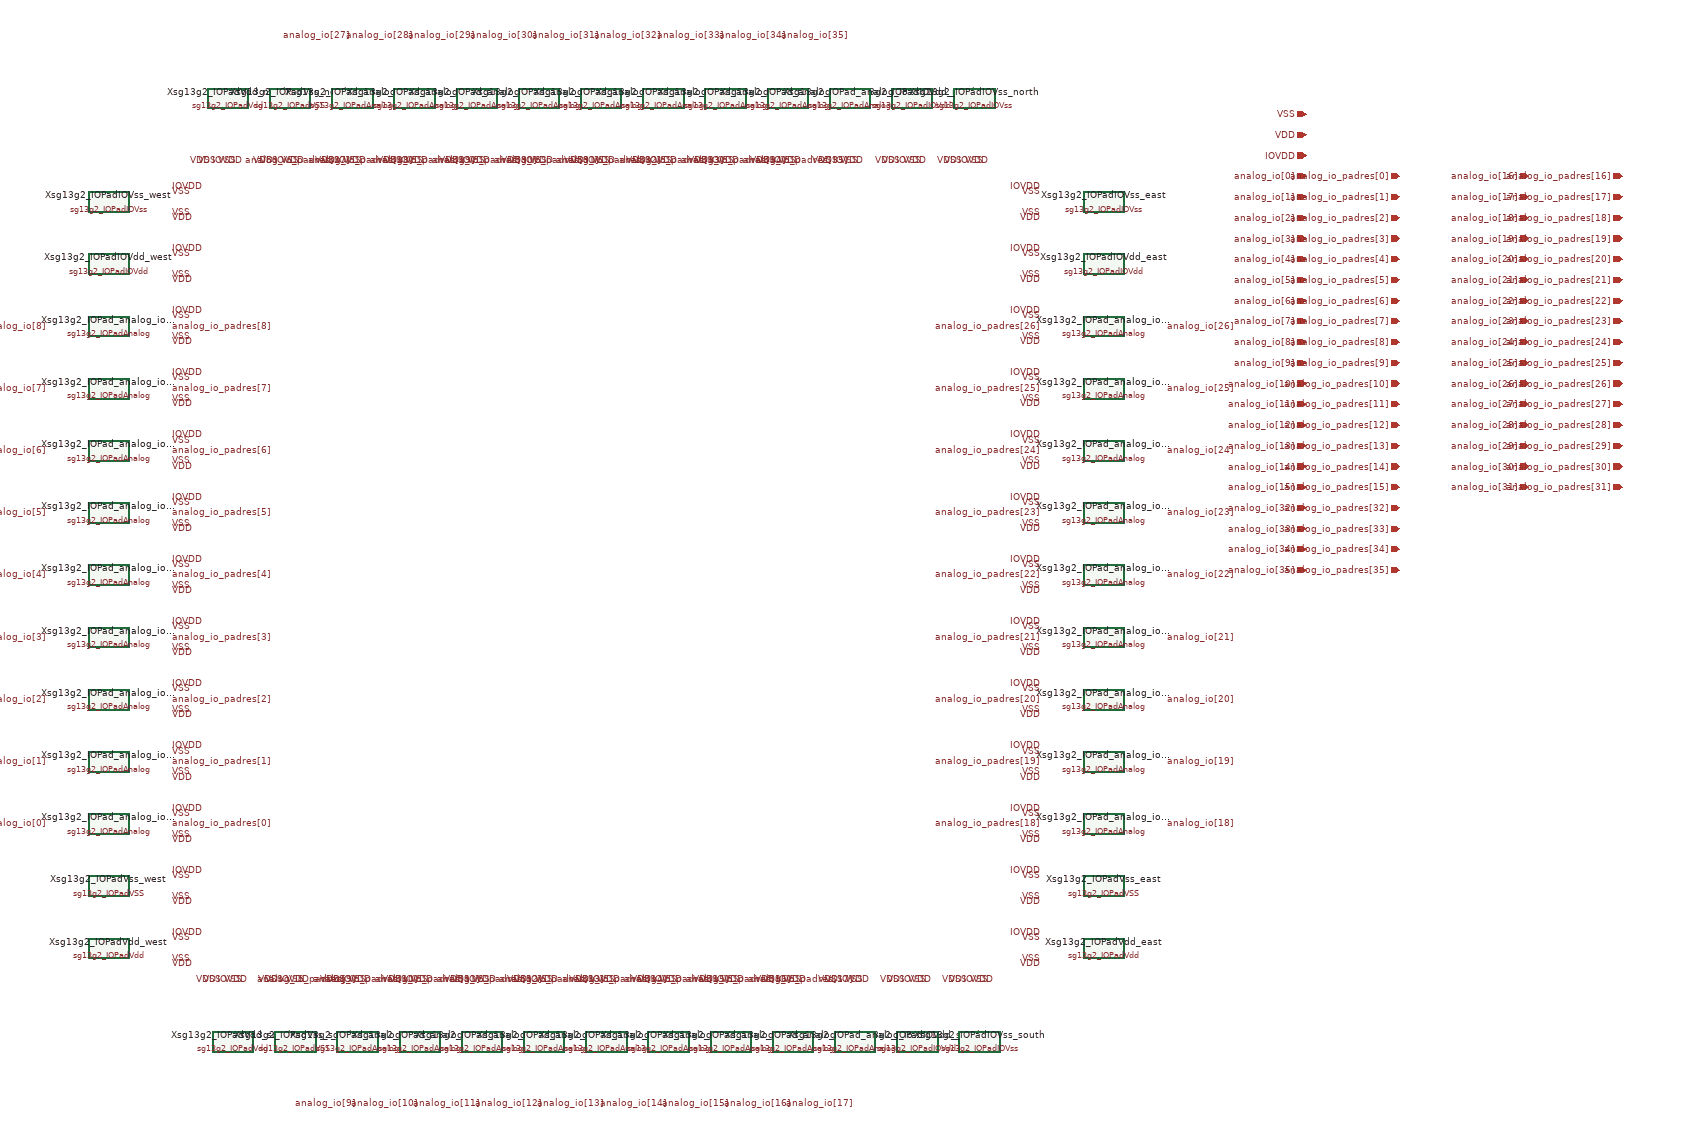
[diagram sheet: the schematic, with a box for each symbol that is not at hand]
v {xschem version=3.4.6 file_version=1.2}
G {}
K {}
V {}
S {}
E {}
C {sg13g2_io/xschem/sg13g2_IOPadVdd.sym} 160 -400 0 1 {name=Xsg13g2_IOPadVdd_west}
C {sg13g2_io/xschem/sg13g2_IOPadVSS.sym} 160 -520 0 1 {name=Xsg13g2_IOPadVss_west}
C {sg13g2_io/xschem/sg13g2_IOPadAnalog.sym} 160 -640 0 1 {name=Xsg13g2_IOPad_analog_io[0]}
C {sg13g2_io/xschem/sg13g2_IOPadAnalog.sym} 160 -760 0 1 {name=Xsg13g2_IOPad_analog_io[1]}
C {sg13g2_io/xschem/sg13g2_IOPadAnalog.sym} 160 -880 0 1 {name=Xsg13g2_IOPad_analog_io[2]}
C {sg13g2_io/xschem/sg13g2_IOPadAnalog.sym} 160 -1000 0 1 {name=Xsg13g2_IOPad_analog_io[3]}
C {sg13g2_io/xschem/sg13g2_IOPadAnalog.sym} 160 -1120 0 1 {name=Xsg13g2_IOPad_analog_io[4]}
C {sg13g2_io/xschem/sg13g2_IOPadAnalog.sym} 160 -1240 0 1 {name=Xsg13g2_IOPad_analog_io[5]}
C {sg13g2_io/xschem/sg13g2_IOPadAnalog.sym} 160 -1360 0 1 {name=Xsg13g2_IOPad_analog_io[6]}
C {sg13g2_io/xschem/sg13g2_IOPadAnalog.sym} 160 -1480 0 1 {name=Xsg13g2_IOPad_analog_io[7]}
C {sg13g2_io/xschem/sg13g2_IOPadIOVdd.sym} 160 -1720 0 1 {name=Xsg13g2_IOPadIOVdd_west}
C {sg13g2_io/xschem/sg13g2_IOPadIOVss.sym} 160 -1840 0 1 {name=Xsg13g2_IOPadIOVss_west}
C {sg13g2_io/xschem/sg13g2_IOPadVdd.sym} 400 -220 1 0 {name=Xsg13g2_IOPadVdd_south}
C {sg13g2_io/xschem/sg13g2_IOPadVSS.sym} 520 -220 1 0 {name=Xsg13g2_IOPadVss_south}
C {sg13g2_io/xschem/sg13g2_IOPadAnalog.sym} 640 -220 1 0 {name=Xsg13g2_IOPad_analog_io[9]}
C {sg13g2_io/xschem/sg13g2_IOPadAnalog.sym} 760 -220 1 0 {name=Xsg13g2_IOPad_analog_io[10]}
C {sg13g2_io/xschem/sg13g2_IOPadAnalog.sym} 880 -220 1 0 {name=Xsg13g2_IOPad_analog_io[11]}
C {sg13g2_io/xschem/sg13g2_IOPadAnalog.sym} 1000 -220 1 0 {name=Xsg13g2_IOPad_analog_io[12]}
C {sg13g2_io/xschem/sg13g2_IOPadAnalog.sym} 1120 -220 1 0 {name=Xsg13g2_IOPad_analog_io[13]}
C {sg13g2_io/xschem/sg13g2_IOPadAnalog.sym} 1240 -220 1 0 {name=Xsg13g2_IOPad_analog_io[14]}
C {sg13g2_io/xschem/sg13g2_IOPadAnalog.sym} 1360 -220 1 0 {name=Xsg13g2_IOPad_analog_io[15]}
C {sg13g2_io/xschem/sg13g2_IOPadIOVdd.sym} 1720 -220 1 0 {name=Xsg13g2_IOPadIOVdd_south}
C {sg13g2_io/xschem/sg13g2_IOPadIOVss.sym} 1840 -220 1 0 {name=Xsg13g2_IOPadIOVss_south}
C {sg13g2_io/xschem/sg13g2_IOPadAnalog.sym} 160 -1600 0 1 {name=Xsg13g2_IOPad_analog_io[8]}
C {sg13g2_io/xschem/sg13g2_IOPadAnalog.sym} 1480 -220 1 0 {name=Xsg13g2_IOPad_analog_io[16]}
C {sg13g2_io/xschem/sg13g2_IOPadAnalog.sym} 1600 -220 1 0 {name=Xsg13g2_IOPad_analog_io[17]}
C {sg13g2_io/xschem/sg13g2_IOPadVdd.sym} 2080 -400 0 0 {name=Xsg13g2_IOPadVdd_east}
C {sg13g2_io/xschem/sg13g2_IOPadVSS.sym} 2080 -520 0 0 {name=Xsg13g2_IOPadVss_east}
C {sg13g2_io/xschem/sg13g2_IOPadAnalog.sym} 2080 -640 0 0 {name=Xsg13g2_IOPad_analog_io[18]}
C {sg13g2_io/xschem/sg13g2_IOPadAnalog.sym} 2080 -760 0 0 {name=Xsg13g2_IOPad_analog_io[19]}
C {sg13g2_io/xschem/sg13g2_IOPadAnalog.sym} 2080 -880 0 0 {name=Xsg13g2_IOPad_analog_io[20]}
C {sg13g2_io/xschem/sg13g2_IOPadAnalog.sym} 2080 -1000 0 0 {name=Xsg13g2_IOPad_analog_io[21]}
C {sg13g2_io/xschem/sg13g2_IOPadAnalog.sym} 2080 -1120 0 0 {name=Xsg13g2_IOPad_analog_io[22]}
C {sg13g2_io/xschem/sg13g2_IOPadAnalog.sym} 2080 -1240 0 0 {name=Xsg13g2_IOPad_analog_io[23]}
C {sg13g2_io/xschem/sg13g2_IOPadAnalog.sym} 2080 -1360 0 0 {name=Xsg13g2_IOPad_analog_io[24]}
C {sg13g2_io/xschem/sg13g2_IOPadAnalog.sym} 2080 -1480 0 0 {name=Xsg13g2_IOPad_analog_io[25]}
C {sg13g2_io/xschem/sg13g2_IOPadIOVdd.sym} 2080 -1720 0 0 {name=Xsg13g2_IOPadIOVdd_east}
C {sg13g2_io/xschem/sg13g2_IOPadIOVss.sym} 2080 -1840 0 0 {name=Xsg13g2_IOPadIOVss_east}
C {sg13g2_io/xschem/sg13g2_IOPadAnalog.sym} 2080 -1600 0 0 {name=Xsg13g2_IOPad_analog_io[26]}
C {sg13g2_io/xschem/sg13g2_IOPadVdd.sym} 390 -2040 1 1 {name=Xsg13g2_IOPadVdd_north}
C {sg13g2_io/xschem/sg13g2_IOPadVSS.sym} 510 -2040 1 1 {name=Xsg13g2_IOPadVss_north}
C {sg13g2_io/xschem/sg13g2_IOPadAnalog.sym} 630 -2040 1 1 {name=Xsg13g2_IOPad_analog_io[28]}
C {sg13g2_io/xschem/sg13g2_IOPadAnalog.sym} 750 -2040 1 1 {name=Xsg13g2_IOPad_analog_io[29]}
C {sg13g2_io/xschem/sg13g2_IOPadAnalog.sym} 870 -2040 1 1 {name=Xsg13g2_IOPad_analog_io[30]}
C {sg13g2_io/xschem/sg13g2_IOPadAnalog.sym} 990 -2040 1 1 {name=Xsg13g2_IOPad_analog_io[31]}
C {sg13g2_io/xschem/sg13g2_IOPadAnalog.sym} 1110 -2040 1 1 {name=Xsg13g2_IOPad_analog_io[32]}
C {sg13g2_io/xschem/sg13g2_IOPadAnalog.sym} 1230 -2040 1 1 {name=Xsg13g2_IOPad_analog_io[33]}
C {sg13g2_io/xschem/sg13g2_IOPadAnalog.sym} 1350 -2040 1 1 {name=Xsg13g2_IOPad_analog_io[34]}
C {sg13g2_io/xschem/sg13g2_IOPadAnalog.sym} 1470 -2040 1 1 {name=Xsg13g2_IOPad_analog_io[35]}
C {sg13g2_io/xschem/sg13g2_IOPadIOVdd.sym} 1710 -2040 1 1 {name=Xsg13g2_IOPadIOVdd_north}
C {sg13g2_io/xschem/sg13g2_IOPadIOVss.sym} 1830 -2040 1 1 {name=Xsg13g2_IOPadIOVss_north}
C {sg13g2_io/xschem/sg13g2_IOPadAnalog.sym} 1590 -2040 1 1 {name=Xsg13g2_IOPad_analog_io[27]}
C {lab_pin.sym} 280 -430 0 1 {name=p1 lab=IOVDD}
C {lab_pin.sym} 280 -420 0 1 {name=p2 lab=VSS}
C {lab_pin.sym} 280 -380 0 1 {name=p3 lab=VSS}
C {lab_pin.sym} 280 -370 0 1 {name=p4 lab=VDD}
C {lab_pin.sym} 280 -550 0 1 {name=p5 lab=IOVDD}
C {lab_pin.sym} 280 -540 0 1 {name=p6 lab=VSS}
C {lab_pin.sym} 280 -500 0 1 {name=p7 lab=VSS}
C {lab_pin.sym} 280 -490 0 1 {name=p8 lab=VDD}
C {lab_pin.sym} 280 -670 0 1 {name=p9 lab=IOVDD}
C {lab_pin.sym} 280 -660 0 1 {name=p10 lab=VSS}
C {lab_pin.sym} 280 -640 0 1 {name=p11 lab=analog_io_padres[0]}
C {lab_pin.sym} 280 -620 0 1 {name=p12 lab=VSS}
C {lab_pin.sym} 280 -610 0 1 {name=p13 lab=VDD}
C {lab_pin.sym} 40 -640 0 0 {name=p14 lab=analog_io[0]}
C {lab_pin.sym} 280 -790 0 1 {name=p15 lab=IOVDD}
C {lab_pin.sym} 280 -780 0 1 {name=p16 lab=VSS}
C {lab_pin.sym} 280 -760 0 1 {name=p17 lab=analog_io_padres[1]}
C {lab_pin.sym} 280 -740 0 1 {name=p18 lab=VSS}
C {lab_pin.sym} 280 -730 0 1 {name=p19 lab=VDD}
C {lab_pin.sym} 40 -760 0 0 {name=p20 lab=analog_io[1]}
C {lab_pin.sym} 280 -910 0 1 {name=p21 lab=IOVDD}
C {lab_pin.sym} 280 -900 0 1 {name=p22 lab=VSS}
C {lab_pin.sym} 280 -880 0 1 {name=p23 lab=analog_io_padres[2]}
C {lab_pin.sym} 280 -860 0 1 {name=p24 lab=VSS}
C {lab_pin.sym} 280 -850 0 1 {name=p25 lab=VDD}
C {lab_pin.sym} 40 -880 0 0 {name=p26 lab=analog_io[2]}
C {lab_pin.sym} 280 -1030 0 1 {name=p27 lab=IOVDD}
C {lab_pin.sym} 280 -1020 0 1 {name=p28 lab=VSS}
C {lab_pin.sym} 280 -1000 0 1 {name=p29 lab=analog_io_padres[3]}
C {lab_pin.sym} 280 -980 0 1 {name=p30 lab=VSS}
C {lab_pin.sym} 280 -970 0 1 {name=p31 lab=VDD}
C {lab_pin.sym} 40 -1000 0 0 {name=p32 lab=analog_io[3]}
C {lab_pin.sym} 280 -1150 0 1 {name=p33 lab=IOVDD}
C {lab_pin.sym} 280 -1140 0 1 {name=p34 lab=VSS}
C {lab_pin.sym} 280 -1120 0 1 {name=p35 lab=analog_io_padres[4]}
C {lab_pin.sym} 280 -1100 0 1 {name=p36 lab=VSS}
C {lab_pin.sym} 280 -1090 0 1 {name=p37 lab=VDD}
C {lab_pin.sym} 40 -1120 0 0 {name=p38 lab=analog_io[4]}
C {lab_pin.sym} 280 -1270 0 1 {name=p39 lab=IOVDD}
C {lab_pin.sym} 280 -1260 0 1 {name=p40 lab=VSS}
C {lab_pin.sym} 280 -1240 0 1 {name=p41 lab=analog_io_padres[5]}
C {lab_pin.sym} 280 -1220 0 1 {name=p42 lab=VSS}
C {lab_pin.sym} 280 -1210 0 1 {name=p43 lab=VDD}
C {lab_pin.sym} 40 -1240 0 0 {name=p44 lab=analog_io[5]}
C {lab_pin.sym} 280 -1390 0 1 {name=p45 lab=IOVDD}
C {lab_pin.sym} 280 -1380 0 1 {name=p46 lab=VSS}
C {lab_pin.sym} 280 -1360 0 1 {name=p47 lab=analog_io_padres[6]}
C {lab_pin.sym} 280 -1340 0 1 {name=p48 lab=VSS}
C {lab_pin.sym} 280 -1330 0 1 {name=p49 lab=VDD}
C {lab_pin.sym} 40 -1360 0 0 {name=p50 lab=analog_io[6]}
C {lab_pin.sym} 280 -1510 0 1 {name=p51 lab=IOVDD}
C {lab_pin.sym} 280 -1500 0 1 {name=p52 lab=VSS}
C {lab_pin.sym} 280 -1480 0 1 {name=p53 lab=analog_io_padres[7]}
C {lab_pin.sym} 280 -1460 0 1 {name=p54 lab=VSS}
C {lab_pin.sym} 280 -1450 0 1 {name=p55 lab=VDD}
C {lab_pin.sym} 40 -1480 0 0 {name=p56 lab=analog_io[7]}
C {lab_pin.sym} 280 -1750 0 1 {name=p57 lab=IOVDD}
C {lab_pin.sym} 280 -1740 0 1 {name=p58 lab=VSS}
C {lab_pin.sym} 280 -1700 0 1 {name=p59 lab=VSS}
C {lab_pin.sym} 280 -1690 0 1 {name=p60 lab=VDD}
C {lab_pin.sym} 280 -1870 0 1 {name=p61 lab=IOVDD}
C {lab_pin.sym} 280 -1860 0 1 {name=p62 lab=VSS}
C {lab_pin.sym} 280 -1820 0 1 {name=p63 lab=VSS}
C {lab_pin.sym} 280 -1810 0 1 {name=p64 lab=VDD}
C {lab_pin.sym} 430 -340 3 1 {name=p65 lab=IOVDD}
C {lab_pin.sym} 420 -340 3 1 {name=p66 lab=VSS}
C {lab_pin.sym} 380 -340 3 1 {name=p67 lab=VSS}
C {lab_pin.sym} 370 -340 3 1 {name=p68 lab=VDD}
C {lab_pin.sym} 550 -340 3 1 {name=p69 lab=IOVDD}
C {lab_pin.sym} 540 -340 3 1 {name=p70 lab=VSS}
C {lab_pin.sym} 500 -340 3 1 {name=p71 lab=VSS}
C {lab_pin.sym} 490 -340 3 1 {name=p72 lab=VDD}
C {lab_pin.sym} 670 -340 3 1 {name=p73 lab=IOVDD}
C {lab_pin.sym} 660 -340 3 1 {name=p74 lab=VSS}
C {lab_pin.sym} 640 -340 3 1 {name=p75 lab=analog_io_padres[9]}
C {lab_pin.sym} 620 -340 3 1 {name=p76 lab=VSS}
C {lab_pin.sym} 610 -340 3 1 {name=p77 lab=VDD}
C {lab_pin.sym} 640 -100 3 0 {name=p78 lab=analog_io[9]}
C {lab_pin.sym} 790 -340 3 1 {name=p79 lab=IOVDD}
C {lab_pin.sym} 780 -340 3 1 {name=p80 lab=VSS}
C {lab_pin.sym} 760 -340 3 1 {name=p81 lab=analog_io_padres[10]}
C {lab_pin.sym} 740 -340 3 1 {name=p82 lab=VSS}
C {lab_pin.sym} 730 -340 3 1 {name=p83 lab=VDD}
C {lab_pin.sym} 760 -100 3 0 {name=p84 lab=analog_io[10]}
C {lab_pin.sym} 910 -340 3 1 {name=p85 lab=IOVDD}
C {lab_pin.sym} 900 -340 3 1 {name=p86 lab=VSS}
C {lab_pin.sym} 880 -340 3 1 {name=p87 lab=analog_io_padres[11]}
C {lab_pin.sym} 860 -340 3 1 {name=p88 lab=VSS}
C {lab_pin.sym} 850 -340 3 1 {name=p89 lab=VDD}
C {lab_pin.sym} 880 -100 3 0 {name=p90 lab=analog_io[11]}
C {lab_pin.sym} 1030 -340 3 1 {name=p91 lab=IOVDD}
C {lab_pin.sym} 1020 -340 3 1 {name=p92 lab=VSS}
C {lab_pin.sym} 1000 -340 3 1 {name=p93 lab=analog_io_padres[12]}
C {lab_pin.sym} 980 -340 3 1 {name=p94 lab=VSS}
C {lab_pin.sym} 970 -340 3 1 {name=p95 lab=VDD}
C {lab_pin.sym} 1000 -100 3 0 {name=p96 lab=analog_io[12]}
C {lab_pin.sym} 1150 -340 3 1 {name=p97 lab=IOVDD}
C {lab_pin.sym} 1140 -340 3 1 {name=p98 lab=VSS}
C {lab_pin.sym} 1120 -340 3 1 {name=p99 lab=analog_io_padres[13]}
C {lab_pin.sym} 1100 -340 3 1 {name=p100 lab=VSS}
C {lab_pin.sym} 1090 -340 3 1 {name=p101 lab=VDD}
C {lab_pin.sym} 1120 -100 3 0 {name=p102 lab=analog_io[13]}
C {lab_pin.sym} 1270 -340 3 1 {name=p103 lab=IOVDD}
C {lab_pin.sym} 1260 -340 3 1 {name=p104 lab=VSS}
C {lab_pin.sym} 1240 -340 3 1 {name=p105 lab=analog_io_padres[14]}
C {lab_pin.sym} 1220 -340 3 1 {name=p106 lab=VSS}
C {lab_pin.sym} 1210 -340 3 1 {name=p107 lab=VDD}
C {lab_pin.sym} 1240 -100 3 0 {name=p108 lab=analog_io[14]}
C {lab_pin.sym} 1390 -340 3 1 {name=p109 lab=IOVDD}
C {lab_pin.sym} 1380 -340 3 1 {name=p110 lab=VSS}
C {lab_pin.sym} 1360 -340 3 1 {name=p111 lab=analog_io_padres[15]}
C {lab_pin.sym} 1340 -340 3 1 {name=p112 lab=VSS}
C {lab_pin.sym} 1330 -340 3 1 {name=p113 lab=VDD}
C {lab_pin.sym} 1360 -100 3 0 {name=p114 lab=analog_io[15]}
C {lab_pin.sym} 1750 -340 3 1 {name=p115 lab=IOVDD}
C {lab_pin.sym} 1740 -340 3 1 {name=p116 lab=VSS}
C {lab_pin.sym} 1700 -340 3 1 {name=p117 lab=VSS}
C {lab_pin.sym} 1690 -340 3 1 {name=p118 lab=VDD}
C {lab_pin.sym} 1870 -340 3 1 {name=p119 lab=IOVDD}
C {lab_pin.sym} 1860 -340 3 1 {name=p120 lab=VSS}
C {lab_pin.sym} 1820 -340 3 1 {name=p121 lab=VSS}
C {lab_pin.sym} 1810 -340 3 1 {name=p122 lab=VDD}
C {lab_pin.sym} 280 -1630 0 1 {name=p123 lab=IOVDD}
C {lab_pin.sym} 280 -1620 0 1 {name=p124 lab=VSS}
C {lab_pin.sym} 280 -1600 0 1 {name=p125 lab=analog_io_padres[8]}
C {lab_pin.sym} 280 -1580 0 1 {name=p126 lab=VSS}
C {lab_pin.sym} 280 -1570 0 1 {name=p127 lab=VDD}
C {lab_pin.sym} 40 -1600 0 0 {name=p128 lab=analog_io[8]}
C {lab_pin.sym} 1510 -340 3 1 {name=p129 lab=IOVDD}
C {lab_pin.sym} 1500 -340 3 1 {name=p130 lab=VSS}
C {lab_pin.sym} 1480 -340 3 1 {name=p131 lab=analog_io_padres[16]}
C {lab_pin.sym} 1460 -340 3 1 {name=p132 lab=VSS}
C {lab_pin.sym} 1450 -340 3 1 {name=p133 lab=VDD}
C {lab_pin.sym} 1480 -100 3 0 {name=p134 lab=analog_io[16]}
C {lab_pin.sym} 1630 -340 3 1 {name=p135 lab=IOVDD}
C {lab_pin.sym} 1620 -340 3 1 {name=p136 lab=VSS}
C {lab_pin.sym} 1600 -340 3 1 {name=p137 lab=analog_io_padres[17]}
C {lab_pin.sym} 1580 -340 3 1 {name=p138 lab=VSS}
C {lab_pin.sym} 1570 -340 3 1 {name=p139 lab=VDD}
C {lab_pin.sym} 1600 -100 3 0 {name=p140 lab=analog_io[17]}
C {lab_pin.sym} 1960 -430 0 0 {name=p141 lab=IOVDD}
C {lab_pin.sym} 1960 -420 0 0 {name=p142 lab=VSS}
C {lab_pin.sym} 1960 -380 0 0 {name=p143 lab=VSS}
C {lab_pin.sym} 1960 -370 0 0 {name=p144 lab=VDD}
C {lab_pin.sym} 1960 -550 0 0 {name=p145 lab=IOVDD}
C {lab_pin.sym} 1960 -540 0 0 {name=p146 lab=VSS}
C {lab_pin.sym} 1960 -500 0 0 {name=p147 lab=VSS}
C {lab_pin.sym} 1960 -490 0 0 {name=p148 lab=VDD}
C {lab_pin.sym} 1960 -670 0 0 {name=p149 lab=IOVDD}
C {lab_pin.sym} 1960 -660 0 0 {name=p150 lab=VSS}
C {lab_pin.sym} 1960 -640 0 0 {name=p151 lab=analog_io_padres[18]}
C {lab_pin.sym} 1960 -620 0 0 {name=p152 lab=VSS}
C {lab_pin.sym} 1960 -610 0 0 {name=p153 lab=VDD}
C {lab_pin.sym} 2200 -640 0 1 {name=p154 lab=analog_io[18]}
C {lab_pin.sym} 1960 -790 0 0 {name=p155 lab=IOVDD}
C {lab_pin.sym} 1960 -780 0 0 {name=p156 lab=VSS}
C {lab_pin.sym} 1960 -760 0 0 {name=p157 lab=analog_io_padres[19]}
C {lab_pin.sym} 1960 -740 0 0 {name=p158 lab=VSS}
C {lab_pin.sym} 1960 -730 0 0 {name=p159 lab=VDD}
C {lab_pin.sym} 2200 -760 0 1 {name=p160 lab=analog_io[19]}
C {lab_pin.sym} 1960 -910 0 0 {name=p161 lab=IOVDD}
C {lab_pin.sym} 1960 -900 0 0 {name=p162 lab=VSS}
C {lab_pin.sym} 1960 -880 0 0 {name=p163 lab=analog_io_padres[20]}
C {lab_pin.sym} 1960 -860 0 0 {name=p164 lab=VSS}
C {lab_pin.sym} 1960 -850 0 0 {name=p165 lab=VDD}
C {lab_pin.sym} 2200 -880 0 1 {name=p166 lab=analog_io[20]}
C {lab_pin.sym} 1960 -1030 0 0 {name=p167 lab=IOVDD}
C {lab_pin.sym} 1960 -1020 0 0 {name=p168 lab=VSS}
C {lab_pin.sym} 1960 -1000 0 0 {name=p169 lab=analog_io_padres[21]}
C {lab_pin.sym} 1960 -980 0 0 {name=p170 lab=VSS}
C {lab_pin.sym} 1960 -970 0 0 {name=p171 lab=VDD}
C {lab_pin.sym} 2200 -1000 0 1 {name=p172 lab=analog_io[21]}
C {lab_pin.sym} 1960 -1150 0 0 {name=p173 lab=IOVDD}
C {lab_pin.sym} 1960 -1140 0 0 {name=p174 lab=VSS}
C {lab_pin.sym} 1960 -1120 0 0 {name=p175 lab=analog_io_padres[22]}
C {lab_pin.sym} 1960 -1100 0 0 {name=p176 lab=VSS}
C {lab_pin.sym} 1960 -1090 0 0 {name=p177 lab=VDD}
C {lab_pin.sym} 2200 -1120 0 1 {name=p178 lab=analog_io[22]}
C {lab_pin.sym} 1960 -1270 0 0 {name=p179 lab=IOVDD}
C {lab_pin.sym} 1960 -1260 0 0 {name=p180 lab=VSS}
C {lab_pin.sym} 1960 -1240 0 0 {name=p181 lab=analog_io_padres[23]}
C {lab_pin.sym} 1960 -1220 0 0 {name=p182 lab=VSS}
C {lab_pin.sym} 1960 -1210 0 0 {name=p183 lab=VDD}
C {lab_pin.sym} 2200 -1240 0 1 {name=p184 lab=analog_io[23]}
C {lab_pin.sym} 1960 -1390 0 0 {name=p185 lab=IOVDD}
C {lab_pin.sym} 1960 -1380 0 0 {name=p186 lab=VSS}
C {lab_pin.sym} 1960 -1360 0 0 {name=p187 lab=analog_io_padres[24]}
C {lab_pin.sym} 1960 -1340 0 0 {name=p188 lab=VSS}
C {lab_pin.sym} 1960 -1330 0 0 {name=p189 lab=VDD}
C {lab_pin.sym} 2200 -1360 0 1 {name=p190 lab=analog_io[24]}
C {lab_pin.sym} 1960 -1510 0 0 {name=p191 lab=IOVDD}
C {lab_pin.sym} 1960 -1500 0 0 {name=p192 lab=VSS}
C {lab_pin.sym} 1960 -1480 0 0 {name=p193 lab=analog_io_padres[25]}
C {lab_pin.sym} 1960 -1460 0 0 {name=p194 lab=VSS}
C {lab_pin.sym} 1960 -1450 0 0 {name=p195 lab=VDD}
C {lab_pin.sym} 2200 -1480 0 1 {name=p196 lab=analog_io[25]}
C {lab_pin.sym} 1960 -1750 0 0 {name=p197 lab=IOVDD}
C {lab_pin.sym} 1960 -1740 0 0 {name=p198 lab=VSS}
C {lab_pin.sym} 1960 -1700 0 0 {name=p199 lab=VSS}
C {lab_pin.sym} 1960 -1690 0 0 {name=p200 lab=VDD}
C {lab_pin.sym} 1960 -1870 0 0 {name=p201 lab=IOVDD}
C {lab_pin.sym} 1960 -1860 0 0 {name=p202 lab=VSS}
C {lab_pin.sym} 1960 -1820 0 0 {name=p203 lab=VSS}
C {lab_pin.sym} 1960 -1810 0 0 {name=p204 lab=VDD}
C {lab_pin.sym} 1960 -1630 0 0 {name=p205 lab=IOVDD}
C {lab_pin.sym} 1960 -1620 0 0 {name=p206 lab=VSS}
C {lab_pin.sym} 1960 -1600 0 0 {name=p207 lab=analog_io_padres[26]}
C {lab_pin.sym} 1960 -1580 0 0 {name=p208 lab=VSS}
C {lab_pin.sym} 1960 -1570 0 0 {name=p209 lab=VDD}
C {lab_pin.sym} 2200 -1600 0 1 {name=p210 lab=analog_io[26]}
C {lab_pin.sym} 420 -1920 3 0 {name=p211 lab=IOVDD}
C {lab_pin.sym} 410 -1920 3 0 {name=p212 lab=VSS}
C {lab_pin.sym} 370 -1920 3 0 {name=p213 lab=VSS}
C {lab_pin.sym} 360 -1920 3 0 {name=p214 lab=VDD}
C {lab_pin.sym} 540 -1920 3 0 {name=p215 lab=IOVDD}
C {lab_pin.sym} 530 -1920 3 0 {name=p216 lab=VSS}
C {lab_pin.sym} 490 -1920 3 0 {name=p217 lab=VSS}
C {lab_pin.sym} 480 -1920 3 0 {name=p218 lab=VDD}
C {lab_pin.sym} 660 -1920 3 0 {name=p219 lab=IOVDD}
C {lab_pin.sym} 650 -1920 3 0 {name=p220 lab=VSS}
C {lab_pin.sym} 630 -1920 3 0 {name=p221 lab=analog_io_padres[27]}
C {lab_pin.sym} 610 -1920 3 0 {name=p222 lab=VSS}
C {lab_pin.sym} 600 -1920 3 0 {name=p223 lab=VDD}
C {lab_pin.sym} 630 -2160 3 1 {name=p224 lab=analog_io[27]}
C {lab_pin.sym} 780 -1920 3 0 {name=p225 lab=IOVDD}
C {lab_pin.sym} 770 -1920 3 0 {name=p226 lab=VSS}
C {lab_pin.sym} 750 -1920 3 0 {name=p227 lab=analog_io_padres[28]}
C {lab_pin.sym} 730 -1920 3 0 {name=p228 lab=VSS}
C {lab_pin.sym} 720 -1920 3 0 {name=p229 lab=VDD}
C {lab_pin.sym} 750 -2160 3 1 {name=p230 lab=analog_io[28]}
C {lab_pin.sym} 900 -1920 3 0 {name=p231 lab=IOVDD}
C {lab_pin.sym} 890 -1920 3 0 {name=p232 lab=VSS}
C {lab_pin.sym} 870 -1920 3 0 {name=p233 lab=analog_io_padres[29]}
C {lab_pin.sym} 850 -1920 3 0 {name=p234 lab=VSS}
C {lab_pin.sym} 840 -1920 3 0 {name=p235 lab=VDD}
C {lab_pin.sym} 870 -2160 3 1 {name=p236 lab=analog_io[29]}
C {lab_pin.sym} 1020 -1920 3 0 {name=p237 lab=IOVDD}
C {lab_pin.sym} 1010 -1920 3 0 {name=p238 lab=VSS}
C {lab_pin.sym} 990 -1920 3 0 {name=p239 lab=analog_io_padres[30]}
C {lab_pin.sym} 970 -1920 3 0 {name=p240 lab=VSS}
C {lab_pin.sym} 960 -1920 3 0 {name=p241 lab=VDD}
C {lab_pin.sym} 990 -2160 3 1 {name=p242 lab=analog_io[30]}
C {lab_pin.sym} 1140 -1920 3 0 {name=p243 lab=IOVDD}
C {lab_pin.sym} 1130 -1920 3 0 {name=p244 lab=VSS}
C {lab_pin.sym} 1110 -1920 3 0 {name=p245 lab=analog_io_padres[31]}
C {lab_pin.sym} 1090 -1920 3 0 {name=p246 lab=VSS}
C {lab_pin.sym} 1080 -1920 3 0 {name=p247 lab=VDD}
C {lab_pin.sym} 1110 -2160 3 1 {name=p248 lab=analog_io[31]}
C {lab_pin.sym} 1260 -1920 3 0 {name=p249 lab=IOVDD}
C {lab_pin.sym} 1250 -1920 3 0 {name=p250 lab=VSS}
C {lab_pin.sym} 1230 -1920 3 0 {name=p251 lab=analog_io_padres[32]}
C {lab_pin.sym} 1210 -1920 3 0 {name=p252 lab=VSS}
C {lab_pin.sym} 1200 -1920 3 0 {name=p253 lab=VDD}
C {lab_pin.sym} 1230 -2160 3 1 {name=p254 lab=analog_io[32]}
C {lab_pin.sym} 1380 -1920 3 0 {name=p255 lab=IOVDD}
C {lab_pin.sym} 1370 -1920 3 0 {name=p256 lab=VSS}
C {lab_pin.sym} 1350 -1920 3 0 {name=p257 lab=analog_io_padres[33]}
C {lab_pin.sym} 1330 -1920 3 0 {name=p258 lab=VSS}
C {lab_pin.sym} 1320 -1920 3 0 {name=p259 lab=VDD}
C {lab_pin.sym} 1350 -2160 3 1 {name=p260 lab=analog_io[33]}
C {lab_pin.sym} 1500 -1920 3 0 {name=p261 lab=IOVDD}
C {lab_pin.sym} 1490 -1920 3 0 {name=p262 lab=VSS}
C {lab_pin.sym} 1470 -1920 3 0 {name=p263 lab=analog_io_padres[34]}
C {lab_pin.sym} 1450 -1920 3 0 {name=p264 lab=VSS}
C {lab_pin.sym} 1440 -1920 3 0 {name=p265 lab=VDD}
C {lab_pin.sym} 1470 -2160 3 1 {name=p266 lab=analog_io[34]}
C {lab_pin.sym} 1740 -1920 3 0 {name=p267 lab=IOVDD}
C {lab_pin.sym} 1730 -1920 3 0 {name=p268 lab=VSS}
C {lab_pin.sym} 1690 -1920 3 0 {name=p269 lab=VSS}
C {lab_pin.sym} 1680 -1920 3 0 {name=p270 lab=VDD}
C {lab_pin.sym} 1860 -1920 3 0 {name=p271 lab=IOVDD}
C {lab_pin.sym} 1850 -1920 3 0 {name=p272 lab=VSS}
C {lab_pin.sym} 1810 -1920 3 0 {name=p273 lab=VSS}
C {lab_pin.sym} 1800 -1920 3 0 {name=p274 lab=VDD}
C {lab_pin.sym} 1620 -1920 3 0 {name=p275 lab=IOVDD}
C {lab_pin.sym} 1610 -1920 3 0 {name=p276 lab=VSS}
C {lab_pin.sym} 1590 -1920 3 0 {name=p277 lab=analog_io_padres[35]}
C {lab_pin.sym} 1570 -1920 3 0 {name=p278 lab=VSS}
C {lab_pin.sym} 1560 -1920 3 0 {name=p279 lab=VDD}
C {lab_pin.sym} 1590 -2160 3 1 {name=p280 lab=analog_io[35]}
C {iopin.sym} 2470 -1970 0 0 {name=p281 lab=VDD}
C {iopin.sym} 2470 -1890 0 0 {name=p283 lab=analog_io[0]}
C {iopin.sym} 2650 -1890 0 0 {name=p284 lab=analog_io_padres[0]}
C {iopin.sym} 2470 -1850 0 0 {name=p285 lab=analog_io[1]}
C {iopin.sym} 2650 -1850 0 0 {name=p286 lab=analog_io_padres[1]}
C {iopin.sym} 2470 -1810 0 0 {name=p283 lab=analog_io[2]}
C {iopin.sym} 2650 -1810 0 0 {name=p284 lab=analog_io_padres[2]}
C {iopin.sym} 2470 -1770 0 0 {name=p285 lab=analog_io[3]}
C {iopin.sym} 2650 -1770 0 0 {name=p286 lab=analog_io_padres[3]}
C {iopin.sym} 2470 -1730 0 0 {name=p283 lab=analog_io[4]}
C {iopin.sym} 2650 -1730 0 0 {name=p284 lab=analog_io_padres[4]}
C {iopin.sym} 2470 -1690 0 0 {name=p285 lab=analog_io[5]}
C {iopin.sym} 2650 -1690 0 0 {name=p286 lab=analog_io_padres[5]}
C {iopin.sym} 2470 -1650 0 0 {name=p285 lab=analog_io[6]}
C {iopin.sym} 2650 -1650 0 0 {name=p286 lab=analog_io_padres[6]}
C {iopin.sym} 2470 -1610 0 0 {name=p283 lab=analog_io[7]}
C {iopin.sym} 2650 -1610 0 0 {name=p284 lab=analog_io_padres[7]}
C {iopin.sym} 2470 -1570 0 0 {name=p285 lab=analog_io[8]}
C {iopin.sym} 2650 -1570 0 0 {name=p286 lab=analog_io_padres[8]}
C {iopin.sym} 2470 -1530 0 0 {name=p283 lab=analog_io[9]}
C {iopin.sym} 2650 -1530 0 0 {name=p284 lab=analog_io_padres[9]}
C {iopin.sym} 2470 -1490 0 0 {name=p285 lab=analog_io[10]}
C {iopin.sym} 2650 -1490 0 0 {name=p286 lab=analog_io_padres[10]}
C {iopin.sym} 2470 -1450 0 0 {name=p285 lab=analog_io[11]}
C {iopin.sym} 2650 -1450 0 0 {name=p286 lab=analog_io_padres[11]}
C {iopin.sym} 2470 -1410 0 0 {name=p283 lab=analog_io[12]}
C {iopin.sym} 2650 -1410 0 0 {name=p284 lab=analog_io_padres[12]}
C {iopin.sym} 2470 -1370 0 0 {name=p285 lab=analog_io[13]}
C {iopin.sym} 2650 -1370 0 0 {name=p286 lab=analog_io_padres[13]}
C {iopin.sym} 2470 -1330 0 0 {name=p283 lab=analog_io[14]}
C {iopin.sym} 2650 -1330 0 0 {name=p284 lab=analog_io_padres[14]}
C {iopin.sym} 2470 -1290 0 0 {name=p285 lab=analog_io[15]}
C {iopin.sym} 2650 -1290 0 0 {name=p286 lab=analog_io_padres[15]}
C {iopin.sym} 2900 -1890 0 0 {name=p287 lab=analog_io[16]}
C {iopin.sym} 3080 -1890 0 0 {name=p288 lab=analog_io_padres[16]}
C {iopin.sym} 2900 -1850 0 0 {name=p289 lab=analog_io[17]}
C {iopin.sym} 3080 -1850 0 0 {name=p290 lab=analog_io_padres[17]}
C {iopin.sym} 2900 -1810 0 0 {name=p291 lab=analog_io[18]}
C {iopin.sym} 3080 -1810 0 0 {name=p292 lab=analog_io_padres[18]}
C {iopin.sym} 2900 -1770 0 0 {name=p293 lab=analog_io[19]}
C {iopin.sym} 3080 -1770 0 0 {name=p294 lab=analog_io_padres[19]}
C {iopin.sym} 2900 -1730 0 0 {name=p295 lab=analog_io[20]}
C {iopin.sym} 3080 -1730 0 0 {name=p296 lab=analog_io_padres[20]}
C {iopin.sym} 2900 -1690 0 0 {name=p297 lab=analog_io[21]}
C {iopin.sym} 3080 -1690 0 0 {name=p298 lab=analog_io_padres[21]}
C {iopin.sym} 2900 -1650 0 0 {name=p299 lab=analog_io[22]}
C {iopin.sym} 3080 -1650 0 0 {name=p300 lab=analog_io_padres[22]}
C {iopin.sym} 2900 -1610 0 0 {name=p301 lab=analog_io[23]}
C {iopin.sym} 3080 -1610 0 0 {name=p302 lab=analog_io_padres[23]}
C {iopin.sym} 2900 -1570 0 0 {name=p303 lab=analog_io[24]}
C {iopin.sym} 3080 -1570 0 0 {name=p304 lab=analog_io_padres[24]}
C {iopin.sym} 2900 -1530 0 0 {name=p305 lab=analog_io[25]}
C {iopin.sym} 3080 -1530 0 0 {name=p306 lab=analog_io_padres[25]}
C {iopin.sym} 2900 -1490 0 0 {name=p307 lab=analog_io[26]}
C {iopin.sym} 3080 -1490 0 0 {name=p308 lab=analog_io_padres[26]}
C {iopin.sym} 2900 -1450 0 0 {name=p309 lab=analog_io[27]}
C {iopin.sym} 3080 -1450 0 0 {name=p310 lab=analog_io_padres[27]}
C {iopin.sym} 2900 -1410 0 0 {name=p311 lab=analog_io[28]}
C {iopin.sym} 3080 -1410 0 0 {name=p312 lab=analog_io_padres[28]}
C {iopin.sym} 2900 -1370 0 0 {name=p313 lab=analog_io[29]}
C {iopin.sym} 3080 -1370 0 0 {name=p314 lab=analog_io_padres[29]}
C {iopin.sym} 2900 -1330 0 0 {name=p315 lab=analog_io[30]}
C {iopin.sym} 3080 -1330 0 0 {name=p316 lab=analog_io_padres[30]}
C {iopin.sym} 2900 -1290 0 0 {name=p317 lab=analog_io[31]}
C {iopin.sym} 3080 -1290 0 0 {name=p318 lab=analog_io_padres[31]}
C {iopin.sym} 2470 -1250 0 0 {name=p319 lab=analog_io[32]}
C {iopin.sym} 2650 -1250 0 0 {name=p320 lab=analog_io_padres[32]}
C {iopin.sym} 2470 -1210 0 0 {name=p321 lab=analog_io[33]}
C {iopin.sym} 2650 -1210 0 0 {name=p322 lab=analog_io_padres[33]}
C {iopin.sym} 2470 -1170 0 0 {name=p323 lab=analog_io[34]}
C {iopin.sym} 2650 -1170 0 0 {name=p324 lab=analog_io_padres[34]}
C {iopin.sym} 2470 -1130 0 0 {name=p325 lab=analog_io[35]}
C {iopin.sym} 2650 -1130 0 0 {name=p326 lab=analog_io_padres[35]}
C {iopin.sym} 2470 -2010 0 0 {name=p334 lab=VSS}
C {iopin.sym} 2470 -1930 0 0 {name=p282 lab=IOVDD}
